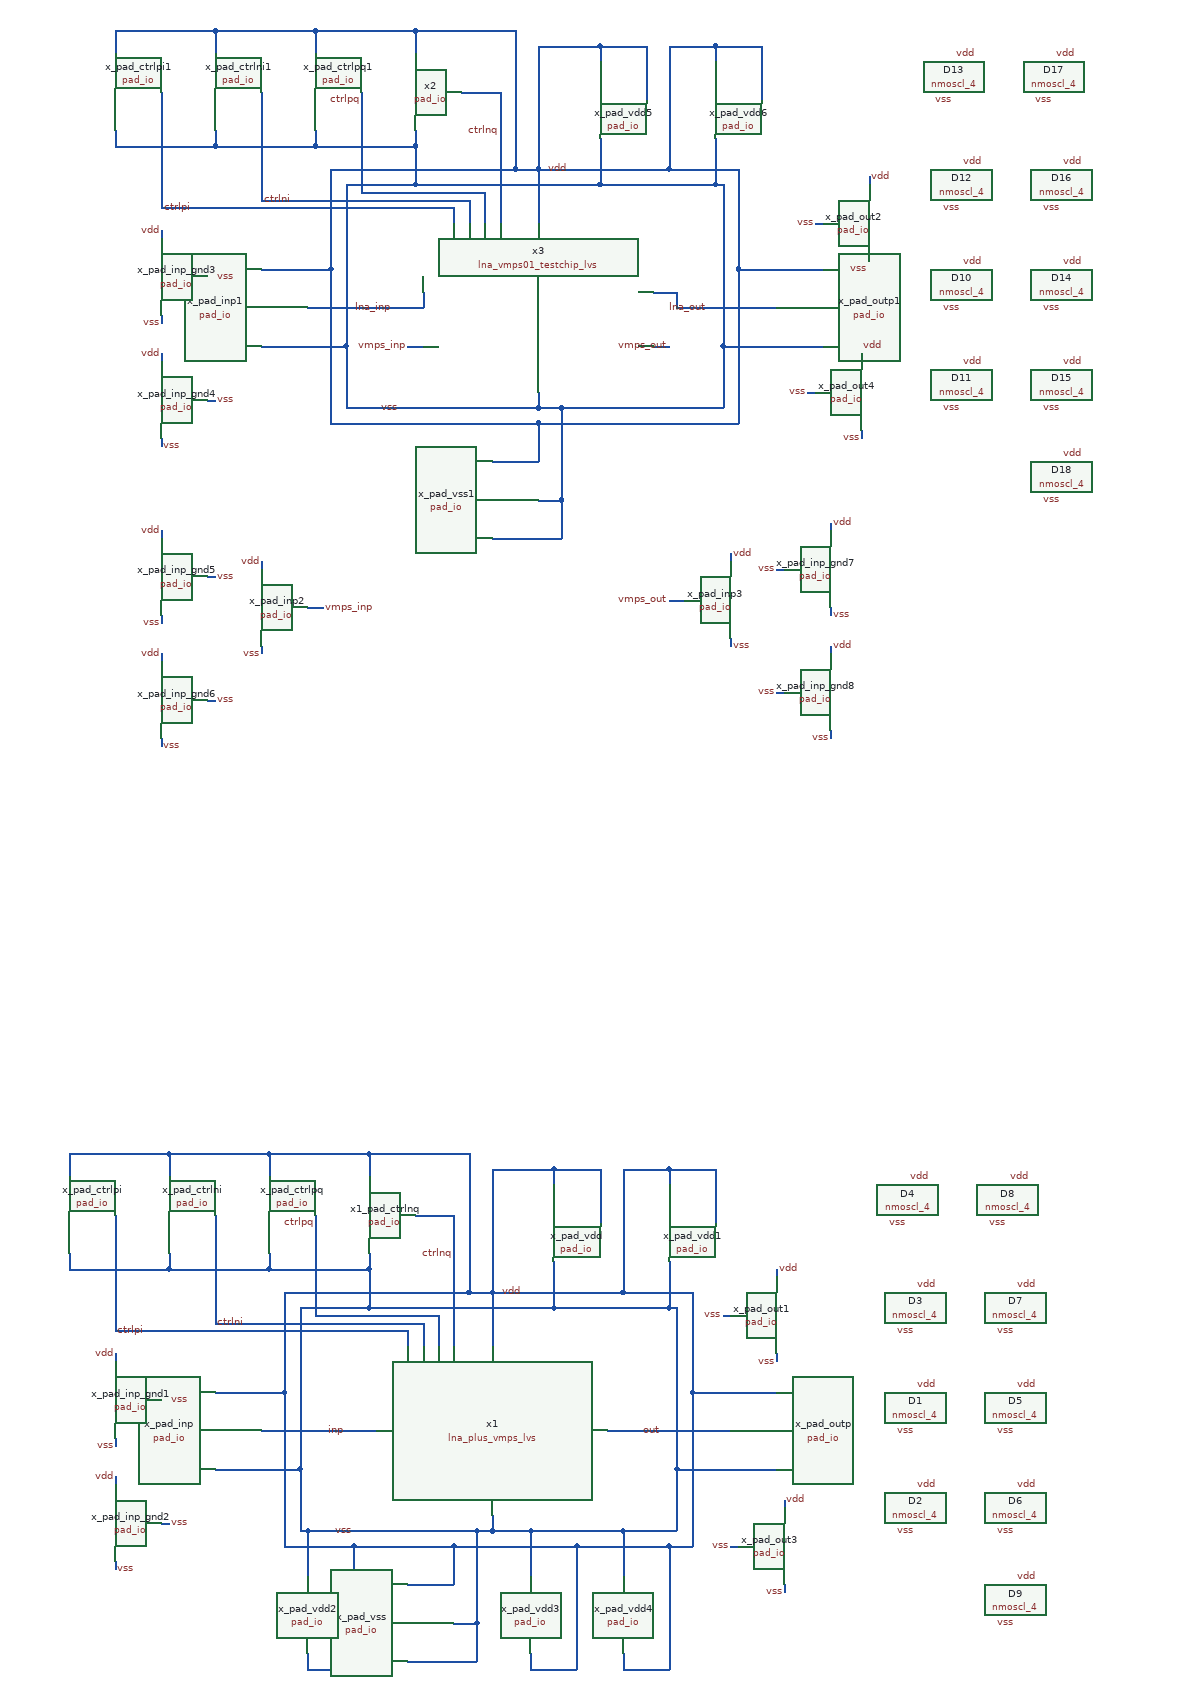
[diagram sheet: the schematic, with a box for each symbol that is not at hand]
v {xschem version=3.4.8RC file_version=1.3}
G {}
K {}
V {}
S {}
F {}
E {}
N 2060 -510 2220 -510 {lab=out}
N 1910 -690 1910 -620 {lab=vdd}
N 1610 -510 1760 -510 {lab=inp}
N 1550 -560 1640 -560 {lab=vdd}
N 1640 -690 1640 -560 {lab=vdd}
N 1880 -690 1910 -690 {lab=vdd}
N 2080 -690 2170 -690 {lab=vdd}
N 1640 -560 1640 -360 {lab=vdd}
N 2170 -560 2280 -560 {lab=vdd}
N 1910 -850 1910 -690 {lab=vdd}
N 1910 -850 1990 -850 {lab=vdd}
N 1990 -850 1990 -830 {lab=vdd}
N 1800 -310 1860 -310 {lab=vdd}
N 1550 -460 1660 -460 {lab=vss}
N 1660 -670 1660 -460 {lab=vss}
N 2140 -670 2150 -670 {lab=vss}
N 1660 -460 1660 -380 {lab=vss}
N 1990 -730 1990 -670 {lab=vss}
N 2150 -460 2280 -460 {lab=vss}
N 2170 -690 2170 -560 {lab=vdd}
N 2150 -670 2150 -460 {lab=vss}
N 2170 -560 2170 -360 {lab=vdd}
N 2150 -460 2150 -380 {lab=vss}
N 1890 -380 1910 -380 {lab=vss}
N 1860 -360 1860 -310 {lab=vdd}
N 2140 -360 2170 -360 {lab=vdd}
N 1910 -400 1910 -380 {lab=vss}
N 1860 -260 1890 -260 {lab=vss}
N 1890 -380 1890 -260 {lab=vss}
N 2080 -380 2150 -380 {lab=vss}
N 1800 -210 1890 -210 {lab=vss}
N 1890 -260 1890 -210 {lab=vss}
N 1990 -850 2050 -850 {lab=vdd}
N 2050 -850 2050 -780 {lab=vdd}
N 1360 -870 1360 -840 {lab=vdd}
N 1620 -870 1750 -870 {lab=vdd}
N 1750 -870 1750 -840 {lab=vdd}
N 1620 -870 1620 -840 {lab=vdd}
N 1490 -870 1620 -870 {lab=vdd}
N 1490 -870 1490 -840 {lab=vdd}
N 1360 -870 1490 -870 {lab=vdd}
N 1750 -870 1880 -870 {lab=vdd}
N 1750 -670 1990 -670 {lab=vss}
N 1360 -740 1360 -720 {lab=vss}
N 1620 -720 1750 -720 {lab=vss}
N 1750 -740 1750 -720 {lab=vss}
N 1490 -740 1490 -720 {lab=vss}
N 1360 -720 1490 -720 {lab=vss}
N 1620 -740 1620 -720 {lab=vss}
N 1490 -720 1620 -720 {lab=vss}
N 1750 -720 1750 -670 {lab=vss}
N 1660 -670 1750 -670 {lab=vss}
N 1880 -870 1880 -690 {lab=vdd}
N 1640 -690 1880 -690 {lab=vdd}
N 1860 -790 1860 -620 {lab=ctrlnq}
N 1810 -790 1860 -790 {lab=ctrlnq}
N 1680 -790 1680 -660 {lab=ctrlpq}
N 1680 -660 1840 -660 {lab=ctrlpq}
N 1840 -660 1840 -620 {lab=ctrlpq}
N 1550 -790 1550 -650 {lab=ctrlni}
N 1550 -650 1820 -650 {lab=ctrlni}
N 1820 -650 1820 -620 {lab=ctrlni}
N 1420 -790 1420 -640 {lab=ctrlpi}
N 1420 -640 1800 -640 {lab=ctrlpi}
N 1800 -640 1800 -620 {lab=ctrlpi}
N 1420 -500 1420 -490 {lab=vss}
N 1480 -550 1490 -550 {lab=vss}
N 1420 -610 1420 -600 {lab=vdd}
N 1420 -450 1420 -440 {lab=vdd}
N 1480 -390 1490 -390 {lab=vss}
N 1420 -340 1420 -330 {lab=vss}
N 2280 -720 2280 -710 {lab=vdd}
N 2210 -660 2220 -660 {lab=vss}
N 2280 -610 2280 -600 {lab=vss}
N 2290 -420 2290 -410 {lab=vdd}
N 2220 -360 2230 -360 {lab=vss}
N 2290 -310 2290 -300 {lab=vss}
N 2140 -850 2140 -830 {lab=vdd}
N 2140 -730 2140 -670 {lab=vss}
N 2140 -850 2200 -850 {lab=vdd}
N 2200 -850 2200 -780 {lab=vdd}
N 1990 -670 2140 -670 {lab=vss}
N 2080 -850 2140 -850 {lab=vdd}
N 2080 -850 2080 -690 {lab=vdd}
N 1910 -690 2080 -690 {lab=vdd}
N 1670 -220 1670 -200 {lab=vdd}
N 1670 -380 1670 -320 {lab=vss}
N 1670 -200 1730 -200 {lab=vdd}
N 1730 -360 1730 -200 {lab=vdd}
N 1660 -380 1670 -380 {lab=vss}
N 1640 -360 1730 -360 {lab=vdd}
N 1730 -360 1860 -360 {lab=vdd}
N 1670 -380 1890 -380 {lab=vss}
N 1960 -220 1960 -200 {lab=vdd}
N 1960 -380 1960 -320 {lab=vss}
N 1960 -200 2020 -200 {lab=vdd}
N 2020 -360 2020 -200 {lab=vdd}
N 1910 -380 1960 -380 {lab=vss}
N 1860 -360 2020 -360 {lab=vdd}
N 2080 -220 2080 -200 {lab=vdd}
N 2080 -380 2080 -320 {lab=vss}
N 2080 -200 2140 -200 {lab=vdd}
N 2140 -360 2140 -200 {lab=vdd}
N 1960 -380 2080 -380 {lab=vss}
N 2020 -360 2140 -360 {lab=vdd}
N 2150 -1970 2280 -1970 {lab=lna_out}
N 1970 -2150 1970 -2080 {lab=vdd}
N 1670 -1970 1820 -1970 {lab=lna_inp}
N 1610 -2020 1700 -2020 {lab=vdd}
N 1700 -2150 1700 -2020 {lab=vdd}
N 1940 -2150 1970 -2150 {lab=vdd}
N 2140 -2150 2230 -2150 {lab=vdd}
N 1970 -1820 2230 -1820 {lab=vdd}
N 1700 -2020 1700 -1820 {lab=vdd}
N 2230 -2020 2340 -2020 {lab=vdd}
N 1970 -2310 1970 -2150 {lab=vdd}
N 1970 -2310 2050 -2310 {lab=vdd}
N 2050 -2310 2050 -2290 {lab=vdd}
N 1910 -1770 1970 -1770 {lab=vdd}
N 1610 -1920 1720 -1920 {lab=vss}
N 1720 -2130 1720 -1920 {lab=vss}
N 2200 -2130 2210 -2130 {lab=vss}
N 2000 -1840 2210 -1840 {lab=vss}
N 1720 -1920 1720 -1840 {lab=vss}
N 2050 -2190 2050 -2130 {lab=vss}
N 2210 -1920 2340 -1920 {lab=vss}
N 2230 -2150 2230 -2020 {lab=vdd}
N 2210 -2130 2210 -1920 {lab=vss}
N 2230 -2020 2230 -1820 {lab=vdd}
N 2210 -1920 2210 -1840 {lab=vss}
N 1720 -1840 1970 -1840 {lab=vss}
N 1970 -1820 1970 -1770 {lab=vdd}
N 1700 -1820 1970 -1820 {lab=vdd}
N 1970 -1860 1970 -1840 {lab=vss}
N 1970 -1720 2000 -1720 {lab=vss}
N 2000 -1840 2000 -1720 {lab=vss}
N 1970 -1840 2000 -1840 {lab=vss}
N 1910 -1670 2000 -1670 {lab=vss}
N 2000 -1720 2000 -1670 {lab=vss}
N 2050 -2310 2110 -2310 {lab=vdd}
N 2110 -2310 2110 -2240 {lab=vdd}
N 1420 -2330 1420 -2300 {lab=vdd}
N 1680 -2330 1810 -2330 {lab=vdd}
N 1810 -2330 1810 -2300 {lab=vdd}
N 1680 -2330 1680 -2300 {lab=vdd}
N 1550 -2330 1680 -2330 {lab=vdd}
N 1550 -2330 1550 -2300 {lab=vdd}
N 1420 -2330 1550 -2330 {lab=vdd}
N 1810 -2330 1940 -2330 {lab=vdd}
N 1810 -2130 2050 -2130 {lab=vss}
N 1420 -2200 1420 -2180 {lab=vss}
N 1680 -2180 1810 -2180 {lab=vss}
N 1810 -2200 1810 -2180 {lab=vss}
N 1550 -2200 1550 -2180 {lab=vss}
N 1420 -2180 1550 -2180 {lab=vss}
N 1680 -2200 1680 -2180 {lab=vss}
N 1550 -2180 1680 -2180 {lab=vss}
N 1810 -2180 1810 -2130 {lab=vss}
N 1720 -2130 1810 -2130 {lab=vss}
N 1940 -2330 1940 -2150 {lab=vdd}
N 1700 -2150 1940 -2150 {lab=vdd}
N 1920 -2250 1920 -2080 {lab=ctrlnq}
N 1870 -2250 1920 -2250 {lab=ctrlnq}
N 1740 -2250 1740 -2120 {lab=ctrlpq}
N 1740 -2120 1900 -2120 {lab=ctrlpq}
N 1900 -2120 1900 -2080 {lab=ctrlpq}
N 1610 -2250 1610 -2110 {lab=ctrlni}
N 1610 -2110 1880 -2110 {lab=ctrlni}
N 1880 -2110 1880 -2080 {lab=ctrlni}
N 1480 -2250 1480 -2100 {lab=ctrlpi}
N 1480 -2100 1860 -2100 {lab=ctrlpi}
N 1860 -2100 1860 -2080 {lab=ctrlpi}
N 1480 -1960 1480 -1950 {lab=vss}
N 1540 -2010 1550 -2010 {lab=vss}
N 1480 -2070 1480 -2060 {lab=vdd}
N 1480 -1910 1480 -1900 {lab=vdd}
N 1540 -1850 1550 -1850 {lab=vss}
N 1480 -1800 1480 -1790 {lab=vss}
N 2400 -2140 2400 -2130 {lab=vdd}
N 2330 -2080 2340 -2080 {lab=vss}
N 2400 -2030 2400 -2020 {lab=vss}
N 2390 -1920 2390 -1910 {lab=vdd}
N 2320 -1860 2330 -1860 {lab=vss}
N 2390 -1810 2390 -1800 {lab=vss}
N 2200 -2310 2200 -2290 {lab=vdd}
N 2200 -2190 2200 -2130 {lab=vss}
N 2200 -2310 2260 -2310 {lab=vdd}
N 2260 -2310 2260 -2240 {lab=vdd}
N 2050 -2130 2200 -2130 {lab=vss}
N 2140 -2310 2200 -2310 {lab=vdd}
N 2140 -2310 2140 -2150 {lab=vdd}
N 1970 -2150 2140 -2150 {lab=vdd}
N 1820 -1990 1820 -1970 {lab=lna_inp}
N 1800 -1920 1820 -1920 {lab=vmps_inp}
N 2120 -1990 2150 -1990 {lab=lna_out}
N 2150 -1990 2150 -1970 {lab=lna_out}
N 2120 -1920 2140 -1920 {lab=vmps_out}
N 1480 -1570 1480 -1560 {lab=vss}
N 1540 -1620 1550 -1620 {lab=vss}
N 1480 -1680 1480 -1670 {lab=vdd}
N 1480 -1520 1480 -1510 {lab=vdd}
N 1540 -1460 1550 -1460 {lab=vss}
N 1480 -1410 1480 -1400 {lab=vss}
N 1610 -1640 1610 -1630 {lab=vdd}
N 1610 -1530 1610 -1520 {lab=vss}
N 1670 -1580 1690 -1580 {lab=vmps_inp}
N 2350 -1580 2350 -1570 {lab=vss}
N 2280 -1630 2290 -1630 {lab=vss}
N 2350 -1690 2350 -1680 {lab=vdd}
N 2350 -1530 2350 -1520 {lab=vdd}
N 2280 -1470 2290 -1470 {lab=vss}
N 2350 -1420 2350 -1410 {lab=vss}
N 2220 -1650 2220 -1640 {lab=vdd}
N 2220 -1540 2220 -1530 {lab=vss}
N 2140 -1590 2160 -1590 {lab=vmps_out}
C {06_integ/pad_io.sym} 1550 -510 0 0 {name=x_pad_inp
}
C {06_integ/pad_io.sym} 1800 -260 0 0 {name=x_pad_vss}
C {06_integ/pad_io.sym} 2280 -510 0 1 {name=x_pad_outp}
C {06_integ/pad_io.sym} 1990 -780 0 0 {name=x_pad_vdd}
C {06_integ/pad_io.sym} 1360 -790 0 0 {name=x_pad_ctrlpi}
C {06_integ/pad_io.sym} 1490 -790 0 0 {name=x_pad_ctrlni}
C {06_integ/pad_io.sym} 1620 -790 0 0 {name=x_pad_ctrlpq}
C {06_integ/pad_io.sym} 1750 -790 0 0 {name=x1_pad_ctrlnq}
C {lab_wire.sym} 1730 -380 0 0 {name=p1 sig_type=std_logic lab=vss}
C {lab_wire.sym} 1720 -510 0 0 {name=p3 sig_type=std_logic lab=inp}
C {lab_wire.sym} 2130 -510 0 0 {name=p4 sig_type=std_logic lab=out}
C {lab_wire.sym} 1950 -690 0 0 {name=p2 sig_type=std_logic lab=vdd}
C {lab_wire.sym} 1460 -640 0 0 {name=p6 sig_type=std_logic lab=ctrlpi}
C {lab_wire.sym} 1590 -650 0 0 {name=p7 sig_type=std_logic lab=ctrlni}
C {lab_wire.sym} 1680 -780 1 1 {name=p8 sig_type=std_logic lab=ctrlpq}
C {lab_wire.sym} 1860 -740 3 1 {name=p9 sig_type=std_logic lab=ctrlnq}
C {06_integ/pad_io.sym} 1420 -550 0 0 {name=x_pad_inp_gnd1
}
C {06_integ/pad_io.sym} 1420 -390 0 0 {name=x_pad_inp_gnd2
}
C {lab_wire.sym} 1420 -610 0 0 {name=p10 sig_type=std_logic lab=vdd}
C {lab_wire.sym} 1420 -490 0 0 {name=p11 sig_type=std_logic lab=vss}
C {lab_wire.sym} 1490 -550 0 1 {name=p12 sig_type=std_logic lab=vss}
C {lab_wire.sym} 1490 -390 0 1 {name=p13 sig_type=std_logic lab=vss}
C {lab_wire.sym} 1420 -330 0 1 {name=p14 sig_type=std_logic lab=vss}
C {lab_wire.sym} 1420 -450 0 0 {name=p15 sig_type=std_logic lab=vdd}
C {06_integ/pad_io.sym} 2280 -660 0 1 {name=x_pad_out1

}
C {lab_wire.sym} 2210 -660 0 0 {name=p16 sig_type=std_logic lab=vss}
C {lab_wire.sym} 2280 -600 0 0 {name=p17 sig_type=std_logic lab=vss}
C {lab_wire.sym} 2280 -720 0 1 {name=p18 sig_type=std_logic lab=vdd}
C {06_integ/pad_io.sym} 2290 -360 0 1 {name=x_pad_out3
}
C {lab_wire.sym} 2220 -360 0 0 {name=p22 sig_type=std_logic lab=vss}
C {lab_wire.sym} 2290 -300 0 0 {name=p23 sig_type=std_logic lab=vss}
C {lab_wire.sym} 2290 -420 0 1 {name=p24 sig_type=std_logic lab=vdd}
C {06_integ/lna_plus_vmps_lvs.sym} 1900 -510 0 0 {name=x1}
C {06_integ/pad_io.sym} 2140 -780 0 0 {name=x_pad_vdd1}
C {sg13g2_pr/nmoscl_4.sym} 2460 -540 0 0 {name=D1
model=nmoscl_4
m=1
spiceprefix=X
}
C {lab_wire.sym} 2460 -570 0 1 {name=p5 sig_type=std_logic lab=vdd}
C {lab_wire.sym} 2460 -510 0 0 {name=p19 sig_type=std_logic lab=vss}
C {sg13g2_pr/nmoscl_4.sym} 2460 -410 0 0 {name=D2
model=nmoscl_4
m=1
spiceprefix=X
}
C {lab_wire.sym} 2460 -440 0 1 {name=p20 sig_type=std_logic lab=vdd}
C {lab_wire.sym} 2460 -380 0 0 {name=p21 sig_type=std_logic lab=vss}
C {sg13g2_pr/nmoscl_4.sym} 2460 -670 0 0 {name=D3
model=nmoscl_4
m=1
spiceprefix=X
}
C {lab_wire.sym} 2460 -700 0 1 {name=p25 sig_type=std_logic lab=vdd}
C {lab_wire.sym} 2460 -640 0 0 {name=p26 sig_type=std_logic lab=vss}
C {sg13g2_pr/nmoscl_4.sym} 2450 -810 0 0 {name=D4
model=nmoscl_4
m=1
spiceprefix=X
}
C {lab_wire.sym} 2450 -840 0 1 {name=p27 sig_type=std_logic lab=vdd}
C {lab_wire.sym} 2450 -780 0 0 {name=p28 sig_type=std_logic lab=vss}
C {sg13g2_pr/nmoscl_4.sym} 2590 -540 0 0 {name=D5
model=nmoscl_4
m=1
spiceprefix=X
}
C {lab_wire.sym} 2590 -570 0 1 {name=p29 sig_type=std_logic lab=vdd}
C {lab_wire.sym} 2590 -510 0 0 {name=p30 sig_type=std_logic lab=vss}
C {sg13g2_pr/nmoscl_4.sym} 2590 -410 0 0 {name=D6
model=nmoscl_4
m=1
spiceprefix=X
}
C {lab_wire.sym} 2590 -440 0 1 {name=p31 sig_type=std_logic lab=vdd}
C {lab_wire.sym} 2590 -380 0 0 {name=p32 sig_type=std_logic lab=vss}
C {sg13g2_pr/nmoscl_4.sym} 2590 -670 0 0 {name=D7
model=nmoscl_4
m=1
spiceprefix=X
}
C {lab_wire.sym} 2590 -700 0 1 {name=p33 sig_type=std_logic lab=vdd}
C {lab_wire.sym} 2590 -640 0 0 {name=p34 sig_type=std_logic lab=vss}
C {sg13g2_pr/nmoscl_4.sym} 2580 -810 0 0 {name=D8
model=nmoscl_4
m=1
spiceprefix=X
}
C {lab_wire.sym} 2580 -840 0 1 {name=p35 sig_type=std_logic lab=vdd}
C {lab_wire.sym} 2580 -780 0 0 {name=p36 sig_type=std_logic lab=vss}
C {sg13g2_pr/nmoscl_4.sym} 2590 -290 0 0 {name=D9
model=nmoscl_4
m=1
spiceprefix=X
}
C {lab_wire.sym} 2590 -320 0 1 {name=p37 sig_type=std_logic lab=vdd}
C {lab_wire.sym} 2590 -260 0 0 {name=p38 sig_type=std_logic lab=vss}
C {06_integ/pad_io.sym} 1670 -270 2 1 {name=x_pad_vdd2}
C {06_integ/pad_io.sym} 1960 -270 2 1 {name=x_pad_vdd3}
C {06_integ/pad_io.sym} 2080 -270 2 1 {name=x_pad_vdd4}
C {06_integ/pad_io.sym} 1610 -1970 0 0 {name=x_pad_inp1
}
C {06_integ/pad_io.sym} 1910 -1720 0 0 {name=x_pad_vss1}
C {06_integ/pad_io.sym} 2340 -1970 0 1 {name=x_pad_outp1}
C {06_integ/pad_io.sym} 2050 -2240 0 0 {name=x_pad_vdd5}
C {06_integ/pad_io.sym} 1420 -2250 0 0 {name=x_pad_ctrlpi1}
C {06_integ/pad_io.sym} 1550 -2250 0 0 {name=x_pad_ctrlni1}
C {06_integ/pad_io.sym} 1680 -2250 0 0 {name=x_pad_ctrlpq1}
C {06_integ/pad_io.sym} 1810 -2250 0 0 {name=x2}
C {lab_wire.sym} 1790 -1840 0 0 {name=p39 sig_type=std_logic lab=vss}
C {lab_wire.sym} 1780 -1970 0 0 {name=p40 sig_type=std_logic lab=lna_inp}
C {lab_wire.sym} 2190 -1970 0 0 {name=p41 sig_type=std_logic lab=lna_out}
C {lab_wire.sym} 2010 -2150 0 0 {name=p42 sig_type=std_logic lab=vdd}
C {lab_wire.sym} 1520 -2100 0 0 {name=p43 sig_type=std_logic lab=ctrlpi}
C {lab_wire.sym} 1650 -2110 0 0 {name=p44 sig_type=std_logic lab=ctrlni}
C {lab_wire.sym} 1740 -2240 1 1 {name=p45 sig_type=std_logic lab=ctrlpq}
C {lab_wire.sym} 1920 -2200 3 1 {name=p46 sig_type=std_logic lab=ctrlnq}
C {06_integ/pad_io.sym} 1480 -2010 0 0 {name=x_pad_inp_gnd3
}
C {06_integ/pad_io.sym} 1480 -1850 0 0 {name=x_pad_inp_gnd4
}
C {lab_wire.sym} 1480 -2070 0 0 {name=p47 sig_type=std_logic lab=vdd}
C {lab_wire.sym} 1480 -1950 0 0 {name=p48 sig_type=std_logic lab=vss}
C {lab_wire.sym} 1550 -2010 0 1 {name=p49 sig_type=std_logic lab=vss}
C {lab_wire.sym} 1550 -1850 0 1 {name=p50 sig_type=std_logic lab=vss}
C {lab_wire.sym} 1480 -1790 0 1 {name=p51 sig_type=std_logic lab=vss}
C {lab_wire.sym} 1480 -1910 0 0 {name=p52 sig_type=std_logic lab=vdd}
C {06_integ/pad_io.sym} 2400 -2080 0 1 {name=x_pad_out2

}
C {lab_wire.sym} 2400 -2020 0 0 {name=p53 sig_type=std_logic lab=vss}
C {lab_wire.sym} 2330 -2080 0 0 {name=p54 sig_type=std_logic lab=vss}
C {lab_wire.sym} 2400 -2140 0 1 {name=p55 sig_type=std_logic lab=vdd}
C {06_integ/pad_io.sym} 2390 -1860 0 1 {name=x_pad_out4
}
C {lab_wire.sym} 2320 -1860 0 0 {name=p56 sig_type=std_logic lab=vss}
C {lab_wire.sym} 2390 -1800 0 0 {name=p57 sig_type=std_logic lab=vss}
C {lab_wire.sym} 2390 -1920 0 1 {name=p58 sig_type=std_logic lab=vdd}
C {06_integ/pad_io.sym} 2200 -2240 0 0 {name=x_pad_vdd6}
C {sg13g2_pr/nmoscl_4.sym} 2520 -2000 0 0 {name=D10
model=nmoscl_4
m=1
spiceprefix=X
}
C {lab_wire.sym} 2520 -2030 0 1 {name=p59 sig_type=std_logic lab=vdd}
C {lab_wire.sym} 2520 -1970 0 0 {name=p60 sig_type=std_logic lab=vss}
C {sg13g2_pr/nmoscl_4.sym} 2520 -1870 0 0 {name=D11
model=nmoscl_4
m=1
spiceprefix=X
}
C {lab_wire.sym} 2520 -1900 0 1 {name=p61 sig_type=std_logic lab=vdd}
C {lab_wire.sym} 2520 -1840 0 0 {name=p62 sig_type=std_logic lab=vss}
C {sg13g2_pr/nmoscl_4.sym} 2520 -2130 0 0 {name=D12
model=nmoscl_4
m=1
spiceprefix=X
}
C {lab_wire.sym} 2520 -2160 0 1 {name=p63 sig_type=std_logic lab=vdd}
C {lab_wire.sym} 2520 -2100 0 0 {name=p64 sig_type=std_logic lab=vss}
C {sg13g2_pr/nmoscl_4.sym} 2510 -2270 0 0 {name=D13
model=nmoscl_4
m=1
spiceprefix=X
}
C {lab_wire.sym} 2510 -2300 0 1 {name=p65 sig_type=std_logic lab=vdd}
C {lab_wire.sym} 2510 -2240 0 0 {name=p66 sig_type=std_logic lab=vss}
C {sg13g2_pr/nmoscl_4.sym} 2650 -2000 0 0 {name=D14
model=nmoscl_4
m=1
spiceprefix=X
}
C {lab_wire.sym} 2650 -2030 0 1 {name=p67 sig_type=std_logic lab=vdd}
C {lab_wire.sym} 2650 -1970 0 0 {name=p68 sig_type=std_logic lab=vss}
C {sg13g2_pr/nmoscl_4.sym} 2650 -1870 0 0 {name=D15
model=nmoscl_4
m=1
spiceprefix=X
}
C {lab_wire.sym} 2650 -1900 0 1 {name=p69 sig_type=std_logic lab=vdd}
C {lab_wire.sym} 2650 -1840 0 0 {name=p70 sig_type=std_logic lab=vss}
C {sg13g2_pr/nmoscl_4.sym} 2650 -2130 0 0 {name=D16
model=nmoscl_4
m=1
spiceprefix=X
}
C {lab_wire.sym} 2650 -2160 0 1 {name=p71 sig_type=std_logic lab=vdd}
C {lab_wire.sym} 2650 -2100 0 0 {name=p72 sig_type=std_logic lab=vss}
C {sg13g2_pr/nmoscl_4.sym} 2640 -2270 0 0 {name=D17
model=nmoscl_4
m=1
spiceprefix=X
}
C {lab_wire.sym} 2640 -2300 0 1 {name=p73 sig_type=std_logic lab=vdd}
C {lab_wire.sym} 2640 -2240 0 0 {name=p74 sig_type=std_logic lab=vss}
C {sg13g2_pr/nmoscl_4.sym} 2650 -1750 0 0 {name=D18
model=nmoscl_4
m=1
spiceprefix=X
}
C {lab_wire.sym} 2650 -1780 0 1 {name=p75 sig_type=std_logic lab=vdd}
C {lab_wire.sym} 2650 -1720 0 0 {name=p76 sig_type=std_logic lab=vss}
C {06_integ/lna_vmps01_testchip_lvs.sym} 1970 -1970 0 0 {name=x3}
C {lab_wire.sym} 1800 -1920 0 0 {name=p77 sig_type=std_logic lab=vmps_inp}
C {lab_wire.sym} 2140 -1920 1 1 {name=p78 sig_type=std_logic lab=vmps_out}
C {06_integ/pad_io.sym} 1610 -1580 0 0 {name=x_pad_inp2
}
C {06_integ/pad_io.sym} 1480 -1620 0 0 {name=x_pad_inp_gnd5
}
C {06_integ/pad_io.sym} 1480 -1460 0 0 {name=x_pad_inp_gnd6
}
C {lab_wire.sym} 1480 -1680 0 0 {name=p79 sig_type=std_logic lab=vdd}
C {lab_wire.sym} 1480 -1560 0 0 {name=p80 sig_type=std_logic lab=vss}
C {lab_wire.sym} 1550 -1620 0 1 {name=p81 sig_type=std_logic lab=vss}
C {lab_wire.sym} 1550 -1460 0 1 {name=p82 sig_type=std_logic lab=vss}
C {lab_wire.sym} 1480 -1400 0 1 {name=p83 sig_type=std_logic lab=vss}
C {lab_wire.sym} 1480 -1520 0 0 {name=p84 sig_type=std_logic lab=vdd}
C {lab_wire.sym} 1610 -1640 0 0 {name=p85 sig_type=std_logic lab=vdd}
C {lab_wire.sym} 1610 -1520 0 0 {name=p86 sig_type=std_logic lab=vss}
C {lab_wire.sym} 1690 -1580 0 1 {name=p87 sig_type=std_logic lab=vmps_inp}
C {06_integ/pad_io.sym} 2220 -1590 0 1 {name=x_pad_inp3
}
C {06_integ/pad_io.sym} 2350 -1630 0 1 {name=x_pad_inp_gnd7
}
C {06_integ/pad_io.sym} 2350 -1470 0 1 {name=x_pad_inp_gnd8
}
C {lab_wire.sym} 2350 -1690 0 1 {name=p88 sig_type=std_logic lab=vdd}
C {lab_wire.sym} 2350 -1570 0 1 {name=p89 sig_type=std_logic lab=vss}
C {lab_wire.sym} 2280 -1630 0 0 {name=p90 sig_type=std_logic lab=vss}
C {lab_wire.sym} 2280 -1470 0 0 {name=p91 sig_type=std_logic lab=vss}
C {lab_wire.sym} 2350 -1410 0 0 {name=p92 sig_type=std_logic lab=vss}
C {lab_wire.sym} 2350 -1530 0 1 {name=p93 sig_type=std_logic lab=vdd}
C {lab_wire.sym} 2220 -1650 0 1 {name=p94 sig_type=std_logic lab=vdd}
C {lab_wire.sym} 2220 -1530 0 1 {name=p95 sig_type=std_logic lab=vss}
C {lab_wire.sym} 2140 -1590 0 0 {name=p96 sig_type=std_logic lab=vmps_out}
